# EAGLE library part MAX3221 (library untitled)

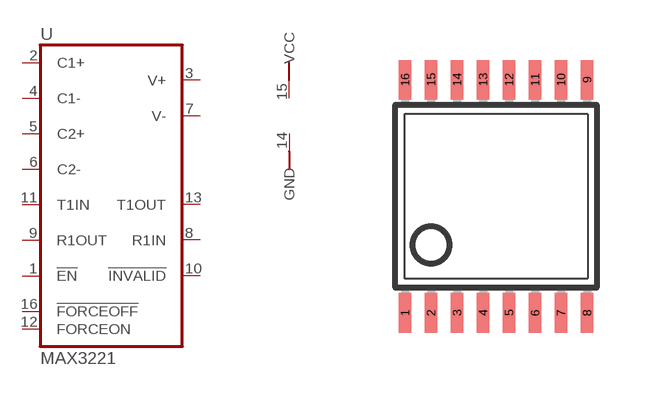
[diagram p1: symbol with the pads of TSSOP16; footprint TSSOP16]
Designator prefix -

## MAX3221  [TSSOP16]
1  !EN  in
2  C1+  pas
3  V+  pas
4  C1-  pas
5  C2+  pas
6  C2-  pas
7  V-  pas
8  R1IN  in
9  R1OUT  out
10  !INVALID  in
11  T1IN  in
12  FORCEON  in
13  T1OUT  out
14  GND  pas
15  VCC  pas
16  !FORCEOFF  in

## Footprint TSSOP16 (pad centres in mm)
Thin Shrink Small Outline Plastic 16 http://www.maxim-ic.com .. MAX3223-MAX3243.pdf
smd 0.305 x 0.991: 1 -2.275,-2.918; 2 -1.625,-2.918; 3 -0.975,-2.918; 4 -0.325,-2.918; 5 0.325,-2.918; 6 0.975,-2.918; 7 1.625,-2.918; 8 2.275,-2.918; 9 2.275,2.918; 10 1.625,2.918; 11 0.975,2.918; 12 0.325,2.918; 13 -0.325,2.918; 14 -0.975,2.918; 15 -1.625,2.918; 16 -2.275,2.918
